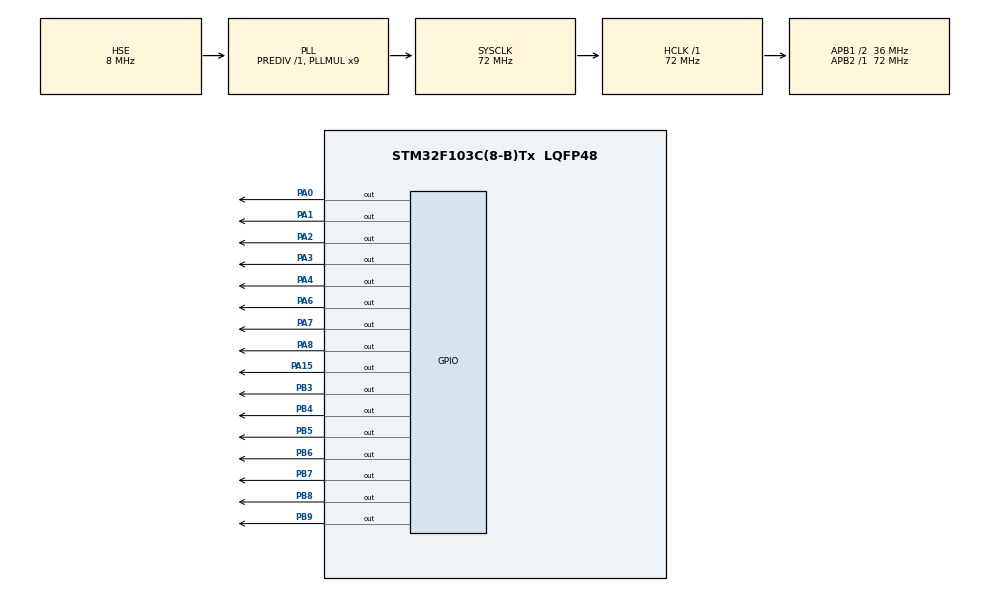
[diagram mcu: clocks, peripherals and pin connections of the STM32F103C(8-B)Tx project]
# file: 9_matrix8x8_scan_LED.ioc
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Mcu.Family=STM32F1
PA2.GPIO_PuPd=GPIO_NOPULL
PA3.GPIO_PuPd=GPIO_NOPULL
PA2.GPIO_Speed=GPIO_SPEED_FREQ_HIGH
PB9.GPIO_ModeDefaultOutputPP=GPIO_MODE_OUTPUT_PP
PA7.GPIO_ModeDefaultOutputPP=GPIO_MODE_OUTPUT_PP
PA3.GPIO_Speed=GPIO_SPEED_FREQ_HIGH
PB3.GPIO_Speed=GPIO_SPEED_FREQ_HIGH
RCC.SYSCLKSource=RCC_SYSCLKSOURCE_PLLCLK
ProjectManager.StackSize=0x400
PD1-OSC_OUT.Signal=RCC_OSC_OUT
PA7.PinState=GPIO_PIN_RESET
RCC.HCLKFreq_Value=72000000
RCC.APB2TimFreq_Value=72000000
PB6.Signal=GPIO_Output
PA1.GPIO_PuPd=GPIO_NOPULL
RCC.AHBFreq_Value=72000000
PA0-WKUP.GPIO_Speed=GPIO_SPEED_FREQ_HIGH
PA4.GPIO_PuPd=GPIO_NOPULL
RCC.PLLMUL=RCC_PLL_MUL9
PA4.GPIO_Speed=GPIO_SPEED_FREQ_HIGH
PA2.PinState=GPIO_PIN_RESET
PA6.GPIO_PuPd=GPIO_NOPULL
PB3.GPIO_PuPd=GPIO_NOPULL
PA14.Mode=Serial_Wire
NVIC.TIM2_IRQn=true\:0\:0\:false\:false\:true\:true\:true
PB7.Signal=GPIO_Output
PA8.Signal=GPIO_Output
PA8.GPIO_ModeDefaultOutputPP=GPIO_MODE_OUTPUT_PP
PA15.GPIO_ModeDefaultOutputPP=GPIO_MODE_OUTPUT_PP
Mcu.Package=LQFP48
PB9.Signal=GPIO_Output
PA6.Signal=GPIO_Output
PA2.GPIO_ModeDefaultOutputPP=GPIO_MODE_OUTPUT_PP
PB6.GPIO_ModeDefaultOutputPP=GPIO_MODE_OUTPUT_PP
PB9.GPIO_PuPd=GPIO_NOPULL
PA15.Signal=GPIO_Output
PA1.PinState=GPIO_PIN_RESET
PB8.GPIO_ModeDefaultOutputPP=GPIO_MODE_OUTPUT_PP
PA4.GPIO_ModeDefaultOutputPP=GPIO_MODE_OUTPUT_PP
PA6.GPIO_ModeDefaultOutputPP=GPIO_MODE_OUTPUT_PP
PB5.GPIO_Speed=GPIO_SPEED_FREQ_HIGH
PB9.GPIO_Speed=GPIO_SPEED_FREQ_HIGH
RCC.APB1TimFreq_Value=72000000
PA6.GPIO_Speed=GPIO_SPEED_FREQ_HIGH
PA8.GPIO_Speed=GPIO_SPEED_FREQ_HIGH
PB4.Signal=GPIO_Output
PB4.GPIO_ModeDefaultOutputPP=GPIO_MODE_OUTPUT_PP
PA3.Signal=GPIO_Output
PB7.GPIO_Speed=GPIO_SPEED_FREQ_HIGH
PB7.GPIO_PuPd=GPIO_NOPULL
RCC.PLLSourceVirtual=RCC_PLLSOURCE_HSE
PB5.GPIO_ModeDefaultOutputPP=GPIO_MODE_OUTPUT_PP
PA0-WKUP.GPIO_ModeDefaultOutputPP=GPIO_MODE_OUTPUT_PP
PA3.GPIO_ModeDefaultOutputPP=GPIO_MODE_OUTPUT_PP
PD1-OSC_OUT.Mode=HSE-External-Oscillator
PB6.GPIO_PuPd=GPIO_NOPULL
PB8.GPIO_PuPd=GPIO_NOPULL
PA6.PinState=GPIO_PIN_RESET
PD0-OSC_IN.Signal=RCC_OSC_IN
RCC.APB1CLKDivider=RCC_HCLK_DIV2
PA0-WKUP.Signal=GPIO_Output
PA13.Signal=SYS_JTMS-SWDIO
PA4.PinState=GPIO_PIN_RESET
ProjectManager.TargetToolchain=STM32CubeIDE
PB4.GPIO_PuPd=GPIO_NOPULL
RCC.USBFreq_Value=72000000
PA7.GPIO_PuPd=GPIO_NOPULL
PA1.Signal=GPIO_Output
PD0-OSC_IN.Mode=HSE-External-Oscillator
board=custom
PA0-WKUP.PinState=GPIO_PIN_RESET
PA7.GPIO_Speed=GPIO_SPEED_FREQ_HIGH
PB4.GPIO_Speed=GPIO_SPEED_FREQ_HIGH
RCC.APB2Freq_Value=72000000
VP_TIM2_VS_ClockSourceINT.Mode=Internal
PB7.GPIO_ModeDefaultOutputPP=GPIO_MODE_OUTPUT_PP
PA1.GPIO_Speed=GPIO_SPEED_FREQ_HIGH
TIM2.Period=36-1
PA13.Mode=Serial_Wire
Mcu.Name=STM32F103C(8-B)Tx
PA2.Signal=GPIO_Output
PB3.Signal=GPIO_Output
PA4.Signal=GPIO_Output
RCC.SYSCLKFreq_VALUE=72000000
PB5.Signal=GPIO_Output
PB5.GPIO_PuPd=GPIO_NOPULL
PA15.GPIO_Speed=GPIO_SPEED_FREQ_HIGH
PA14.Signal=SYS_JTCK-SWCLK
ProjectManager.HeapSize=0x200
NVIC.PriorityGroup=NVIC_PRIORITYGROUP_4
PA15.GPIO_PuPd=GPIO_NOPULL
PB8.Signal=GPIO_Output
PA0-WKUP.GPIO_PuPd=GPIO_NOPULL
PA3.PinState=GPIO_PIN_RESET
PB6.GPIO_Speed=GPIO_SPEED_FREQ_HIGH
RCC.APB1Freq_Value=36000000
PB8.GPIO_Speed=GPIO_SPEED_FREQ_HIGH
PB3.GPIO_ModeDefaultOutputPP=GPIO_MODE_OUTPUT_PP
PA7.Signal=GPIO_Output
PA1.GPIO_ModeDefaultOutputPP=GPIO_MODE_OUTPUT_PP

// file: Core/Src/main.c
/* USER CODE BEGIN Header */
/**
 ******************************************************************************
 * @file           : main.c
 * @brief          : Main program body
 ******************************************************************************
 * @attention
 *
 * <h2><center>&copy; Copyright (c) 2021 STMicroelectronics.
 * All rights reserved.</center></h2>
 *
 * This software component is licensed by ST under BSD 3-Clause license,
 * the "License"; You may not use this file except in compliance with the
 * License. You may obtain a copy of the License at:
 *                        opensource.org/licenses/BSD-3-Clause
 *
 ******************************************************************************
 */
/* USER CODE END Header */
#include "main.h"

/* USER CODE BEGIN Includes */
#include "matrix8x8.h"
/* USER CODE END Includes */

TIM_HandleTypeDef htim2;

/* USER CODE BEGIN PV */
//HAL_GPIO_WritePin(GPIO_TypeDef *GPIOx, uint16_t GPIO_Pin, GPIO_PinState PinState)

/* USER CODE END PV */

void SystemClock_Config(void);
static void MX_GPIO_Init(void);
static void MX_TIM2_Init(void);

/* USER CODE BEGIN 0 */
volatile uint32_t cntTimer;
volatile uint32_t mSecond;
uint16_t ms = 0;
void HAL_TIM_PeriodElapsedCallback(TIM_HandleTypeDef *htim)
{
	if(htim->Instance == TIM2)
	{
		if(cntTimer>0)
		{
			cntTimer--;
			HAL_TIM_Base_Start_IT(&htim2);
		}
		else
		HAL_TIM_Base_Stop_IT(&htim2);
	}
}
void Delay_us(uint32_t _cntTimer)
{
	cntTimer = _cntTimer;
	HAL_TIM_Base_Start_IT(&htim2);
	while(cntTimer);
}
__weak void SysTick_Handler(void)
{
  /* USER CODE BEGIN SysTick_IRQn 0 */

  /* USER CODE END SysTick_IRQn 0 */
	if(ms<2000)
	{
		ms++;
	}
	else
	{
		ms = 0;
		if(mSecond<37)
			mSecond++;
		else
			mSecond = 0;
	}
  HAL_IncTick();
  /* USER CODE BEGIN SysTick_IRQn 1 */

  /* USER CODE END SysTick_IRQn 1 */
}
/* USER CODE END 0 */

int main(void)
{

  /* MCU Configuration--------------------------------------------------------*/

  /* Reset of all peripherals, Initializes the Flash interface and the Systick. */
  HAL_Init();

  /* USER CODE BEGIN Init */
	//HAL_GPIO_WritePin(GPIOx, GPIO_Pin, PinState)
  /* USER CODE END Init */

  /* Configure the system clock */
  SystemClock_Config();

  /* Initialize all configured peripherals */
  MX_GPIO_Init();
  MX_TIM2_Init();
  /* USER CODE BEGIN 2 */
//  HAL_GPIO_WritePin(GPIOA, R6_Pin, GPIO_PIN_SET);//ROW 1 HIGH
//  HAL_GPIO_WritePin(GPIOA, R5_Pin, GPIO_PIN_SET);//ROW 1 HIGH
//
//  HAL_GPIO_WritePin(GPIOB, C6_Pin, GPIO_PIN_SET);//ROW 1 HIGH
  /* USER CODE END 2 */

  /* Infinite loop */
	while (1) {

    /* USER CODE BEGIN 3 */
		Matrix8x8_ShiftLR(0);
	}
  /* USER CODE END 3 */
}

void SystemClock_Config(void)
{
  RCC_OscInitTypeDef RCC_OscInitStruct = {0};
  RCC_ClkInitTypeDef RCC_ClkInitStruct = {0};

  /** Initializes the RCC Oscillators according to the specified parameters
  * in the RCC_OscInitTypeDef structure.
  */
  RCC_OscInitStruct.OscillatorType = RCC_OSCILLATORTYPE_HSE;
  RCC_OscInitStruct.HSEState = RCC_HSE_ON;
  RCC_OscInitStruct.HSEPredivValue = RCC_HSE_PREDIV_DIV1;
  RCC_OscInitStruct.HSIState = RCC_HSI_ON;
  RCC_OscInitStruct.PLL.PLLState = RCC_PLL_ON;
  RCC_OscInitStruct.PLL.PLLSource = RCC_PLLSOURCE_HSE;
  RCC_OscInitStruct.PLL.PLLMUL = RCC_PLL_MUL9;
  if (HAL_RCC_OscConfig(&RCC_OscInitStruct) != HAL_OK)
  {
    Error_Handler();
  }
  /** Initializes the CPU, AHB and APB buses clocks
  */
  RCC_ClkInitStruct.ClockType = RCC_CLOCKTYPE_HCLK|RCC_CLOCKTYPE_SYSCLK
                              |RCC_CLOCKTYPE_PCLK1|RCC_CLOCKTYPE_PCLK2;
  RCC_ClkInitStruct.SYSCLKSource = RCC_SYSCLKSOURCE_PLLCLK;
  RCC_ClkInitStruct.AHBCLKDivider = RCC_SYSCLK_DIV1;
  RCC_ClkInitStruct.APB1CLKDivider = RCC_HCLK_DIV2;
  RCC_ClkInitStruct.APB2CLKDivider = RCC_HCLK_DIV1;

  if (HAL_RCC_ClockConfig(&RCC_ClkInitStruct, FLASH_LATENCY_2) != HAL_OK)
  {
    Error_Handler();
  }
}

static void MX_TIM2_Init(void)
{

  TIM_ClockConfigTypeDef sClockSourceConfig = {0};
  TIM_MasterConfigTypeDef sMasterConfig = {0};

  htim2.Instance = TIM2;
  htim2.Init.Prescaler = 0;
  htim2.Init.CounterMode = TIM_COUNTERMODE_UP;
  htim2.Init.Period = 36-1;
  htim2.Init.ClockDivision = TIM_CLOCKDIVISION_DIV1;
  htim2.Init.AutoReloadPreload = TIM_AUTORELOAD_PRELOAD_DISABLE;
  if (HAL_TIM_Base_Init(&htim2) != HAL_OK)
  {
    Error_Handler();
  }
  sClockSourceConfig.ClockSource = TIM_CLOCKSOURCE_INTERNAL;
  if (HAL_TIM_ConfigClockSource(&htim2, &sClockSourceConfig) != HAL_OK)
  {
    Error_Handler();
  }
  sMasterConfig.MasterOutputTrigger = TIM_TRGO_RESET;
  sMasterConfig.MasterSlaveMode = TIM_MASTERSLAVEMODE_DISABLE;
  if (HAL_TIMEx_MasterConfigSynchronization(&htim2, &sMasterConfig) != HAL_OK)
  {
    Error_Handler();
  }

}

static void MX_GPIO_Init(void)
{
  GPIO_InitTypeDef GPIO_InitStruct = {0};

  /* GPIO Ports Clock Enable */
  __HAL_RCC_GPIOD_CLK_ENABLE();
  __HAL_RCC_GPIOA_CLK_ENABLE();
  __HAL_RCC_GPIOB_CLK_ENABLE();

  /*Configure GPIO pin Output Level */
  HAL_GPIO_WritePin(GPIOA, GPIO_PIN_0|GPIO_PIN_1|GPIO_PIN_2|GPIO_PIN_3
                          |GPIO_PIN_4|GPIO_PIN_5|GPIO_PIN_6|GPIO_PIN_7, GPIO_PIN_RESET);

  /*Configure GPIO pin Output Level */
  HAL_GPIO_WritePin(GPIOB, GPIO_PIN_0|GPIO_PIN_1|GPIO_PIN_3|GPIO_PIN_4
                          |GPIO_PIN_5|GPIO_PIN_6|GPIO_PIN_7|GPIO_PIN_8, GPIO_PIN_RESET);

  /*Configure GPIO pins : PA0 PA1 PA2 PA3
                           PA4 PA5 PA6 PA7 */
  GPIO_InitStruct.Pin = GPIO_PIN_0|GPIO_PIN_1|GPIO_PIN_2|GPIO_PIN_3
                          |GPIO_PIN_4|GPIO_PIN_5|GPIO_PIN_6|GPIO_PIN_7;
  GPIO_InitStruct.Mode = GPIO_MODE_OUTPUT_PP;
  GPIO_InitStruct.Pull = GPIO_NOPULL;
  GPIO_InitStruct.Speed = GPIO_SPEED_FREQ_HIGH;
  HAL_GPIO_Init(GPIOA, &GPIO_InitStruct);

  /*Configure GPIO pins : PB0 PB1 PB3 PB4
                           PB5 PB6 PB7 PB8 */
  GPIO_InitStruct.Pin = GPIO_PIN_0|GPIO_PIN_1|GPIO_PIN_3|GPIO_PIN_4
                          |GPIO_PIN_5|GPIO_PIN_6|GPIO_PIN_7|GPIO_PIN_8;
  GPIO_InitStruct.Mode = GPIO_MODE_OUTPUT_PP;
  GPIO_InitStruct.Pull = GPIO_NOPULL;
  GPIO_InitStruct.Speed = GPIO_SPEED_FREQ_HIGH;
  HAL_GPIO_Init(GPIOB, &GPIO_InitStruct);

}

void Error_Handler(void)
{
	__disable_irq();
	while (1) {
	}
}

/************************ (C) COPYRIGHT STMicroelectronics *****END OF FILE****/
